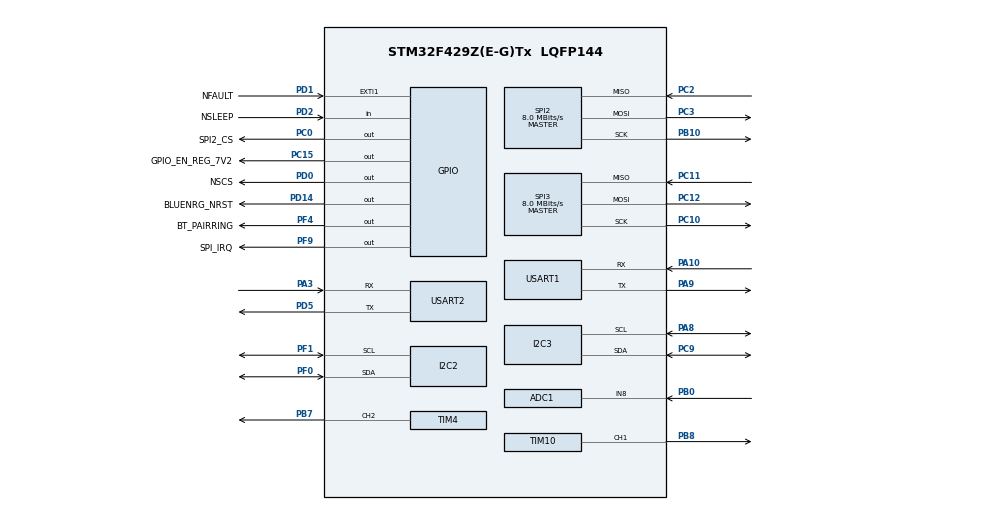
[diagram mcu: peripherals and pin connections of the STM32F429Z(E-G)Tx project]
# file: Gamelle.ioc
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ADC1.Channel-10\#ChannelRegularConversion=ADC_CHANNEL_8
ADC1.NbrOfConversionFlag=1
ADC1.Rank-10\#ChannelRegularConversion=1
ADC1.SamplingTime-10\#ChannelRegularConversion=ADC_SAMPLETIME_3CYCLES
ADC1.master=1
Mcu.Family=STM32F4
Mcu.Name=STM32F429Z(E-G)Tx
Mcu.Package=LQFP144
NVIC.PriorityGroup=NVIC_PRIORITYGROUP_4
PA10.Mode=Asynchronous
PA10.Signal=USART1_RX
PA13.Mode=JTAG_5_pins
PA13.Signal=SYS_JTMS-SWDIO
PA14.Mode=JTAG_5_pins
PA14.Signal=SYS_JTCK-SWCLK
PA15.Mode=JTAG_5_pins
PA15.Signal=SYS_JTDI
PA3.Mode=Asynchronous
PA3.Signal=USART2_RX
PA8.Mode=I2C
PA8.Signal=I2C3_SCL
PA9.Mode=Asynchronous
PA9.Signal=USART1_TX
PB0.Signal=ADCx_IN8
PB10.Mode=Full_Duplex_Master
PB10.Signal=SPI2_SCK
PB3.Mode=JTAG_5_pins
PB3.Signal=SYS_JTDO-SWO
PB4.Mode=JTAG_5_pins
PB4.Signal=SYS_JTRST
PB7.Signal=S_TIM4_CH2
PB8.Signal=S_TIM10_CH1
PC0.GPIO_Label=SPI2_CS
PC0.Signal=GPIO_Output
PC10.Mode=Full_Duplex_Master
PC10.Signal=SPI3_SCK
PC11.Mode=Full_Duplex_Master
PC11.Signal=SPI3_MISO
PC12.Mode=Full_Duplex_Master
PC12.Signal=SPI3_MOSI
PC15/OSC32_OUT.GPIO_Label=GPIO_EN_REG_7V2
PC15/OSC32_OUT.Signal=GPIO_Output
PC2.Mode=Full_Duplex_Master
PC2.Signal=SPI2_MISO
PC3.Mode=Full_Duplex_Master
PC3.Signal=SPI2_MOSI
PC9.Mode=I2C
PC9.Signal=I2C3_SDA
PD0.GPIO_Label=NSCS
PD0.Signal=GPIO_Output
PD1.GPIO_Label=NFAULT
PD1.Signal=GPXTI1
PD14.GPIO_Label=BLUENRG_NRST
PD14.Signal=GPIO_Output
PD2.GPIO_Label=NSLEEP
PD2.Signal=GPIO_Input
PD5.Mode=Asynchronous
PD5.Signal=USART2_TX
PF0.Mode=I2C
PF0.Signal=I2C2_SDA
PF1.Mode=I2C
PF1.Signal=I2C2_SCL
PF4.GPIO_Label=BT_PAIRRING
PF4.Signal=GPIO_Output
PF9.GPIO_Label=SPI_IRQ
PF9.Signal=GPIO_Output
PH0/OSC_IN.Signal=RCC_OSC_IN
PH1/OSC_OUT.Signal=RCC_OSC_OUT
ProjectManager.HeapSize=0x200
ProjectManager.StackSize=0x400
ProjectManager.TargetToolchain=EWARM V8.50
RCC.AHBFreq_Value=16000000
RCC.APB1Freq_Value=16000000
RCC.APB2Freq_Value=16000000
RCC.CortexFreq_Value=16000000
RCC.HSE_VALUE=25000000
RCC.HSI_VALUE=16000000
RCC.LSE_VALUE=32768
RCC.SYSCLKFreq_VALUE=16000000
RCC.VCOOutputFreq_Value=192000000
SH.ADCx_IN8.0=ADC1_IN8,IN8
SH.S_TIM10_CH1.0=TIM10_CH1,PWM Generation1 CH1
SH.S_TIM4_CH2.0=TIM4_CH2,PWM Generation2 CH2
SPI2.CalculateBaudRate=8.0 MBits/s
SPI2.Direction=SPI_DIRECTION_2LINES
SPI2.Mode=SPI_MODE_MASTER
SPI2.VirtualType=VM_MASTER
SPI3.CalculateBaudRate=8.0 MBits/s
SPI3.Direction=SPI_DIRECTION_2LINES
SPI3.Mode=SPI_MODE_MASTER
SPI3.VirtualType=VM_MASTER
TIM10.Channel=TIM_CHANNEL_1
TIM4.Channel-PWM\ Generation2\ CH2=TIM_CHANNEL_2
USART1.VirtualMode=VM_ASYNC
USART2.VirtualMode=VM_ASYNC
VP_TIM10_VS_ClockSourceINT.Mode=Enable_Timer
board=custom

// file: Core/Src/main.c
/* USER CODE BEGIN Header */
/**
  ******************************************************************************
  * @file           : main.c
  * @brief          : Main program body
  ******************************************************************************
  * @attention
  *
  * Copyright (c) 2023 STMicroelectronics.
  * All rights reserved.
  *
  * This software is licensed under terms that can be found in the LICENSE file
  * in the root directory of this software component.
  * If no LICENSE file comes with this software, it is provided AS-IS.
  *
  ******************************************************************************
  */
/* USER CODE END Header */
#include "main.h"
#include "adc.h"
#include "i2c.h"
#include "spi.h"
#include "tim.h"
#include "usart.h"
#include "gpio.h"

void SystemClock_Config(void);

int main(void)
{

  /* MCU Configuration--------------------------------------------------------*/

  /* Reset of all peripherals, Initializes the Flash interface and the Systick. */
  HAL_Init();

  /* Configure the system clock */
  SystemClock_Config();

  /* Initialize all configured peripherals */
  MX_GPIO_Init();
  MX_SPI2_Init();
  MX_I2C2_Init();
  MX_USART1_UART_Init();
  MX_USART2_UART_Init();
  MX_ADC1_Init();
  MX_I2C3_Init();
  MX_SPI3_Init();
  MX_TIM4_Init();
  MX_TIM10_Init();

  /* Infinite loop */
  while (1)
  {

  }
}

void SystemClock_Config(void)
{
  RCC_OscInitTypeDef RCC_OscInitStruct = {0};
  RCC_ClkInitTypeDef RCC_ClkInitStruct = {0};

  /** Configure the main internal regulator output voltage
  */
  __HAL_RCC_PWR_CLK_ENABLE();
  __HAL_PWR_VOLTAGESCALING_CONFIG(PWR_REGULATOR_VOLTAGE_SCALE1);

  /** Initializes the RCC Oscillators according to the specified parameters
  * in the RCC_OscInitTypeDef structure.
  */
  RCC_OscInitStruct.OscillatorType = RCC_OSCILLATORTYPE_HSI;
  RCC_OscInitStruct.HSIState = RCC_HSI_ON;
  RCC_OscInitStruct.HSICalibrationValue = RCC_HSICALIBRATION_DEFAULT;
  RCC_OscInitStruct.PLL.PLLState = RCC_PLL_ON;
  RCC_OscInitStruct.PLL.PLLSource = RCC_PLLSOURCE_HSI;
  RCC_OscInitStruct.PLL.PLLM = 8;
  RCC_OscInitStruct.PLL.PLLN = 180;
  RCC_OscInitStruct.PLL.PLLP = RCC_PLLP_DIV2;
  RCC_OscInitStruct.PLL.PLLQ = 4;
  if (HAL_RCC_OscConfig(&RCC_OscInitStruct) != HAL_OK)
  {
    Error_Handler();
  }

  /** Activate the Over-Drive mode
  */
  if (HAL_PWREx_EnableOverDrive() != HAL_OK)
  {
    Error_Handler();
  }

  /** Initializes the CPU, AHB and APB buses clocks
  */
  RCC_ClkInitStruct.ClockType = RCC_CLOCKTYPE_HCLK|RCC_CLOCKTYPE_SYSCLK
                              |RCC_CLOCKTYPE_PCLK1|RCC_CLOCKTYPE_PCLK2;
  RCC_ClkInitStruct.SYSCLKSource = RCC_SYSCLKSOURCE_PLLCLK;
  RCC_ClkInitStruct.AHBCLKDivider = RCC_SYSCLK_DIV1;
  RCC_ClkInitStruct.APB1CLKDivider = RCC_HCLK_DIV4;
  RCC_ClkInitStruct.APB2CLKDivider = RCC_HCLK_DIV2;

  if (HAL_RCC_ClockConfig(&RCC_ClkInitStruct, FLASH_LATENCY_5) != HAL_OK)
  {
    Error_Handler();
  }
}

void Error_Handler(void)
{
  __disable_irq();
  while (1)
  {
  }
}
